One B-rep face of a CAD part: STEP entity #17633.
In plain terms, the planar face has unit normal (1, 0, 0).
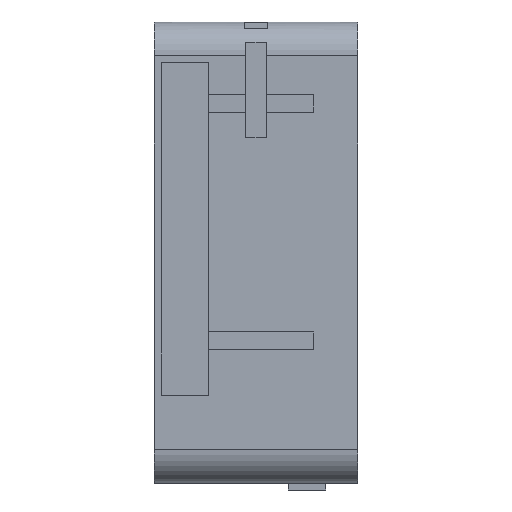
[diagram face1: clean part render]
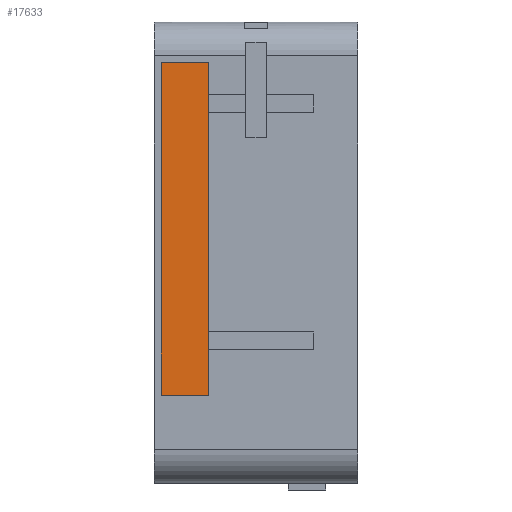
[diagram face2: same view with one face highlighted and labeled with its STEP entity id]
Its self-contained STEP definition (entity closure, numbers rounded to 3 decimals):
#4111 = PLANE('',#4112);
#4112 = AXIS2_PLACEMENT_3D('',#4113,#4114,#4115);
#4113 = CARTESIAN_POINT('',(25.,-21.,22.));
#4114 = DIRECTION('',(0.,0.,1.));
#4115 = DIRECTION('',(1.,0.,-0.));
#4139 = PLANE('',#4140);
#4140 = AXIS2_PLACEMENT_3D('',#4141,#4142,#4143);
#4141 = CARTESIAN_POINT('',(25.,28.,22.));
#4142 = DIRECTION('',(-0.,1.,0.));
#4143 = DIRECTION('',(0.,0.,1.));
#4167 = PLANE('',#4168);
#4168 = AXIS2_PLACEMENT_3D('',#4169,#4170,#4171);
#4169 = CARTESIAN_POINT('',(25.,-21.,29.));
#4170 = DIRECTION('',(0.,0.,1.));
#4171 = DIRECTION('',(1.,0.,-0.));
#4195 = PLANE('',#4196);
#4196 = AXIS2_PLACEMENT_3D('',#4197,#4198,#4199);
#4197 = CARTESIAN_POINT('',(25.,-21.,22.));
#4198 = DIRECTION('',(-0.,1.,0.));
#4199 = DIRECTION('',(0.,0.,1.));
#10572 = VERTEX_POINT('',#10573);
#10573 = CARTESIAN_POINT('',(26.,-21.,22.));
#10594 = EDGE_CURVE('',#10572,#10595,#10597,.T.);
#10595 = VERTEX_POINT('',#10596);
#10596 = CARTESIAN_POINT('',(26.,28.,22.));
#10597 = SURFACE_CURVE('',#10598,(#10602,#10609),.PCURVE_S1.);
#10598 = LINE('',#10599,#10600);
#10599 = CARTESIAN_POINT('',(26.,-21.,22.));
#10600 = VECTOR('',#10601,1.);
#10601 = DIRECTION('',(-0.,1.,0.));
#10602 = PCURVE('',#4111,#10603);
#10603 = DEFINITIONAL_REPRESENTATION('',(#10604),#10608);
#10604 = LINE('',#10605,#10606);
#10605 = CARTESIAN_POINT('',(1.,0.));
#10606 = VECTOR('',#10607,1.);
#10607 = DIRECTION('',(0.,1.));
#10608 = ( GEOMETRIC_REPRESENTATION_CONTEXT(2) 
PARAMETRIC_REPRESENTATION_CONTEXT() REPRESENTATION_CONTEXT('2D SPACE',''
  ) );
#10609 = PCURVE('',#10610,#10615);
#10610 = PLANE('',#10611);
#10611 = AXIS2_PLACEMENT_3D('',#10612,#10613,#10614);
#10612 = CARTESIAN_POINT('',(26.,-21.,22.));
#10613 = DIRECTION('',(1.,0.,-0.));
#10614 = DIRECTION('',(0.,0.,1.));
#10615 = DEFINITIONAL_REPRESENTATION('',(#10616),#10620);
#10616 = LINE('',#10617,#10618);
#10617 = CARTESIAN_POINT('',(0.,0.));
#10618 = VECTOR('',#10619,1.);
#10619 = DIRECTION('',(0.,-1.));
#10620 = ( GEOMETRIC_REPRESENTATION_CONTEXT(2) 
PARAMETRIC_REPRESENTATION_CONTEXT() REPRESENTATION_CONTEXT('2D SPACE',''
  ) );
#10883 = VERTEX_POINT('',#10884);
#10884 = CARTESIAN_POINT('',(26.,-21.,29.));
#10905 = EDGE_CURVE('',#10572,#10883,#10906,.T.);
#10906 = SURFACE_CURVE('',#10907,(#10911,#10918),.PCURVE_S1.);
#10907 = LINE('',#10908,#10909);
#10908 = CARTESIAN_POINT('',(26.,-21.,22.));
#10909 = VECTOR('',#10910,1.);
#10910 = DIRECTION('',(0.,0.,1.));
#10911 = PCURVE('',#4195,#10912);
#10912 = DEFINITIONAL_REPRESENTATION('',(#10913),#10917);
#10913 = LINE('',#10914,#10915);
#10914 = CARTESIAN_POINT('',(0.,1.));
#10915 = VECTOR('',#10916,1.);
#10916 = DIRECTION('',(1.,0.));
#10917 = ( GEOMETRIC_REPRESENTATION_CONTEXT(2) 
PARAMETRIC_REPRESENTATION_CONTEXT() REPRESENTATION_CONTEXT('2D SPACE',''
  ) );
#10918 = PCURVE('',#10610,#10919);
#10919 = DEFINITIONAL_REPRESENTATION('',(#10920),#10924);
#10920 = LINE('',#10921,#10922);
#10921 = CARTESIAN_POINT('',(0.,0.));
#10922 = VECTOR('',#10923,1.);
#10923 = DIRECTION('',(1.,0.));
#10924 = ( GEOMETRIC_REPRESENTATION_CONTEXT(2) 
PARAMETRIC_REPRESENTATION_CONTEXT() REPRESENTATION_CONTEXT('2D SPACE',''
  ) );
#10931 = EDGE_CURVE('',#10883,#10932,#10934,.T.);
#10932 = VERTEX_POINT('',#10933);
#10933 = CARTESIAN_POINT('',(26.,28.,29.));
#10934 = SURFACE_CURVE('',#10935,(#10939,#10946),.PCURVE_S1.);
#10935 = LINE('',#10936,#10937);
#10936 = CARTESIAN_POINT('',(26.,-21.,29.));
#10937 = VECTOR('',#10938,1.);
#10938 = DIRECTION('',(-0.,1.,0.));
#10939 = PCURVE('',#4167,#10940);
#10940 = DEFINITIONAL_REPRESENTATION('',(#10941),#10945);
#10941 = LINE('',#10942,#10943);
#10942 = CARTESIAN_POINT('',(1.,0.));
#10943 = VECTOR('',#10944,1.);
#10944 = DIRECTION('',(0.,1.));
#10945 = ( GEOMETRIC_REPRESENTATION_CONTEXT(2) 
PARAMETRIC_REPRESENTATION_CONTEXT() REPRESENTATION_CONTEXT('2D SPACE',''
  ) );
#10946 = PCURVE('',#10610,#10947);
#10947 = DEFINITIONAL_REPRESENTATION('',(#10948),#10952);
#10948 = LINE('',#10949,#10950);
#10949 = CARTESIAN_POINT('',(7.,0.));
#10950 = VECTOR('',#10951,1.);
#10951 = DIRECTION('',(0.,-1.));
#10952 = ( GEOMETRIC_REPRESENTATION_CONTEXT(2) 
PARAMETRIC_REPRESENTATION_CONTEXT() REPRESENTATION_CONTEXT('2D SPACE',''
  ) );
#10981 = EDGE_CURVE('',#10595,#10932,#10982,.T.);
#10982 = SURFACE_CURVE('',#10983,(#10987,#10994),.PCURVE_S1.);
#10983 = LINE('',#10984,#10985);
#10984 = CARTESIAN_POINT('',(26.,28.,22.));
#10985 = VECTOR('',#10986,1.);
#10986 = DIRECTION('',(0.,0.,1.));
#10987 = PCURVE('',#4139,#10988);
#10988 = DEFINITIONAL_REPRESENTATION('',(#10989),#10993);
#10989 = LINE('',#10990,#10991);
#10990 = CARTESIAN_POINT('',(0.,1.));
#10991 = VECTOR('',#10992,1.);
#10992 = DIRECTION('',(1.,0.));
#10993 = ( GEOMETRIC_REPRESENTATION_CONTEXT(2) 
PARAMETRIC_REPRESENTATION_CONTEXT() REPRESENTATION_CONTEXT('2D SPACE',''
  ) );
#10994 = PCURVE('',#10610,#10995);
#10995 = DEFINITIONAL_REPRESENTATION('',(#10996),#11000);
#10996 = LINE('',#10997,#10998);
#10997 = CARTESIAN_POINT('',(0.,-49.));
#10998 = VECTOR('',#10999,1.);
#10999 = DIRECTION('',(1.,0.));
#11000 = ( GEOMETRIC_REPRESENTATION_CONTEXT(2) 
PARAMETRIC_REPRESENTATION_CONTEXT() REPRESENTATION_CONTEXT('2D SPACE',''
  ) );
#17633 = ADVANCED_FACE('',(#17634),#10610,.T.);
#17634 = FACE_BOUND('',#17635,.T.);
#17635 = EDGE_LOOP('',(#17636,#17637,#17638,#17639));
#17636 = ORIENTED_EDGE('',*,*,#10905,.F.);
#17637 = ORIENTED_EDGE('',*,*,#10594,.T.);
#17638 = ORIENTED_EDGE('',*,*,#10981,.T.);
#17639 = ORIENTED_EDGE('',*,*,#10931,.F.);
